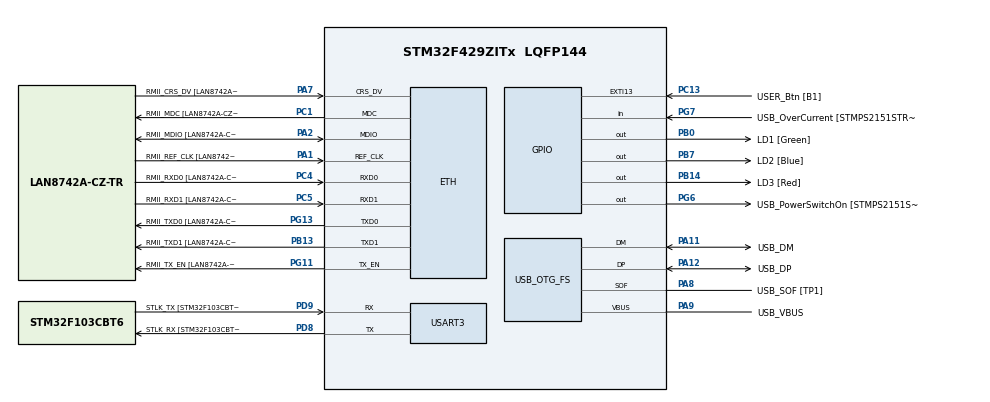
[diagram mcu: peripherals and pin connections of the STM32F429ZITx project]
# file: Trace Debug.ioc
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ETH.MediaInterface=ETH_MEDIA_INTERFACE_RMII
ETH.PHY_Name=LAN8742A_PHY_ADDRESS
ETH.PHY_Value=0
ETH.PhyAddress=0
Mcu.Family=STM32F4
Mcu.Name=STM32F429ZITx
Mcu.Package=LQFP144
NVIC.PriorityGroup=NVIC_PRIORITYGROUP_4
PA1.GPIO_Label=RMII_REF_CLK [LAN8742A-CZ-TR_REFCLK0]
PA1.Mode=RMII
PA1.Signal=ETH_REF_CLK
PA10.GPIO_Label=USB_ID
PA10.Signal=USB_OTG_FS_ID
PA11.GPIO_Label=USB_DM
PA11.Mode=Device_Only
PA11.Signal=USB_OTG_FS_DM
PA12.GPIO_Label=USB_DP
PA12.Mode=Device_Only
PA12.Signal=USB_OTG_FS_DP
PA13.GPIO_Label=TMS
PA13.Mode=Trace_Asynchronous_SW
PA13.Signal=SYS_JTMS-SWDIO
PA14.GPIO_Label=TCK
PA14.Mode=Trace_Asynchronous_SW
PA14.Signal=SYS_JTCK-SWCLK
PA2.GPIO_Label=RMII_MDIO [LAN8742A-CZ-TR_MDIO]
PA2.Mode=RMII
PA2.Signal=ETH_MDIO
PA7.GPIO_Label=RMII_CRS_DV [LAN8742A-CZ-TR_CRS_DV]
PA7.Mode=RMII
PA7.Signal=ETH_CRS_DV
PA8.GPIO_Label=USB_SOF [TP1]
PA8.Mode=Activate_SOF_FS
PA8.Signal=USB_OTG_FS_SOF
PA9.GPIO_Label=USB_VBUS
PA9.Mode=Activate_VBUS
PA9.Signal=USB_OTG_FS_VBUS
PB0.GPIO_Label=LD1 [Green]
PB0.Signal=GPIO_Output
PB13.GPIO_Label=RMII_TXD1 [LAN8742A-CZ-TR_TXD1]
PB13.Mode=RMII
PB13.Signal=ETH_TXD1
PB14.GPIO_Label=LD3 [Red]
PB14.Signal=GPIO_Output
PB3.Mode=Trace_Asynchronous_SW
PB3.Signal=SYS_JTDO-SWO
PB7.GPIO_Label=LD2 [Blue]
PB7.Signal=GPIO_Output
PC1.GPIO_Label=RMII_MDC [LAN8742A-CZ-TR_MDC]
PC1.Mode=RMII
PC1.Signal=ETH_MDC
PC13.GPIO_Label=USER_Btn [B1]
PC13.Signal=GPXTI13
PC14/OSC32_IN.Mode=LSE-External-Oscillator
PC14/OSC32_IN.Signal=RCC_OSC32_IN
PC15/OSC32_OUT.Mode=LSE-External-Oscillator
PC15/OSC32_OUT.Signal=RCC_OSC32_OUT
PC4.GPIO_Label=RMII_RXD0 [LAN8742A-CZ-TR_RXD0]
PC4.Mode=RMII
PC4.Signal=ETH_RXD0
PC5.GPIO_Label=RMII_RXD1 [LAN8742A-CZ-TR_RXD1]
PC5.Mode=RMII
PC5.Signal=ETH_RXD1
PD8.GPIO_Label=STLK_RX [STM32F103CBT6_PA3]
PD8.Mode=Asynchronous
PD8.Signal=USART3_TX
PD9.GPIO_Label=STLK_TX [STM32F103CBT6_PA2]
PD9.Mode=Asynchronous
PD9.Signal=USART3_RX
PG11.GPIO_Label=RMII_TX_EN [LAN8742A-CZ-TR_TXEN]
PG11.Mode=RMII
PG11.Signal=ETH_TX_EN
PG13.GPIO_Label=RMII_TXD0 [LAN8742A-CZ-TR_TXD0]
PG13.Mode=RMII
PG13.Signal=ETH_TXD0
PG6.GPIO_Label=USB_PowerSwitchOn [STMPS2151STR_EN]
PG6.Signal=GPIO_Output
PG7.GPIO_Label=USB_OverCurrent [STMPS2151STR_FAULT]
PG7.Signal=GPIO_Input
PH0/OSC_IN.GPIO_Label=MCO [STM32F103CBT6_PA8]
PH0/OSC_IN.Mode=HSE-External-Clock-Source
PH0/OSC_IN.Signal=RCC_OSC_IN
PH1/OSC_OUT.Mode=HSE-External-Clock-Source
PH1/OSC_OUT.Signal=RCC_OSC_OUT
ProjectManager.HeapSize=0x800
ProjectManager.StackSize=0x800
ProjectManager.TargetToolchain=STM32CubeIDE
RCC.48MHZClocksFreq_Value=48000000
RCC.AHBFreq_Value=168000000
RCC.APB1CLKDivider=RCC_HCLK_DIV4
RCC.APB1Freq_Value=42000000
RCC.APB1TimFreq_Value=84000000
RCC.APB2CLKDivider=RCC_HCLK_DIV2
RCC.APB2Freq_Value=84000000
RCC.APB2TimCLKDivider=2
RCC.APB2TimFreq_Value=168000000
RCC.CortexFreq_Value=168000000
RCC.HCLKFreq_Value=168000000
RCC.HSE_VALUE=8000000
RCC.HSI_VALUE=16000000
RCC.PLLM=4
RCC.PLLMUL=RCC_PLL_MUL9
RCC.PLLN=168
RCC.PLLQ=7
RCC.PRESCALERUSB=RCC_USBCLKSOURCE_PLL_DIV1_5
RCC.SYSCLKFreq_VALUE=168000000
RCC.SYSCLKSource=RCC_SYSCLKSOURCE_PLLCLK
RCC.SYSCLKSourceVirtual=RCC_SYSCLKSOURCE_PLLCLK
RCC.USBFreq_Value=48000000
RCC.VCOOutputFreq_Value=336000000
USART3.VirtualMode=VM_ASYNC
USB_OTG_FS.VirtualMode=Device_Only
board=NUCLEO-F429ZI

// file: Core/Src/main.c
/* USER CODE BEGIN Header */
/**
  ******************************************************************************
  * @file           : main.c
  * @brief          : Main program body
  ******************************************************************************
  * @attention
  *
  * <h2><center>&copy; Copyright (c) 2022 STMicroelectronics.
  * All rights reserved.</center></h2>
  *
  * This software component is licensed by ST under BSD 3-Clause license,
  * the "License"; You may not use this file except in compliance with the
  * License. You may obtain a copy of the License at:
  *                        opensource.org/licenses/BSD-3-Clause
  *
  ******************************************************************************
  */
/* USER CODE END Header */
#include "main.h"
#include "Modules/cramel.h"
#include "dwt_counter.h"
#include "math_helper.h"

ETH_HandleTypeDef heth;

UART_HandleTypeDef huart3;

PCD_HandleTypeDef hpcd_USB_OTG_FS;

void SystemClock_Config(void);
static void MX_GPIO_Init(void);
static void MX_USART3_UART_Init(void);

/* USER CODE BEGIN 0 */
int16_t s16_curfitLine[RX_LEN];
float f32_curfitLine[RX_LEN];

#ifdef SWO_DEBUG
	//make sure SWV core clock MHz same as CPU clock.
	//SWV viewer setting debug port 1 are checked, and started

	int _write(int file, char *ptr, int len)
	{
		int i=0;
		for(i=0; i<len; i++){
			ITM_SendChar(*ptr++);
		}
		return len;
	}

#else
#ifdef __GNUC__
	/* With GCC, small printf (option LD Linker->Libraries->Small printf set to 'Yes') calls __io_putchar() */
	#define PUTCHAR_PROTOTYPE int __io_putchar(int ch)
	#else
	#define PUTCHAR_PROTOTYPE int fputc(int ch, FILE *f)
	#endif /* __GNUC__ */

	/******************************************************************
	  * @name   PUTCHAR_PROTOTYPE
	  * @brief  Retargets the C library printf function to the USART.
	  *****************************************************************/
	PUTCHAR_PROTOTYPE
	{
		HAL_UART_Transmit(&huart3, (uint8_t *)&ch, 1, 0xFFFF);				//Use USART3
		return ch;
	}

#endif

/* USER CODE END 0 */

int main(void)
{
  /* USER CODE BEGIN 1 */
  curfitCoef_t curfitCoef;
  uint64_t u64_bitmap;

  int16_t *s16_src;
  uint8_t *u8_curfitComp;
  float *f32_curfitLineRef;
  float f32_snr;
  float f32_accuracy;
  volatile float f32_duration = 0;
  volatile float f32_accuracyFrame = 0;
  /* USER CODE END 1 */

  /* MCU Configuration--------------------------------------------------------*/

  /* Reset of all peripherals, Initializes the Flash interface and the Systick. */
  HAL_Init();

  /* Configure the system clock */
  SystemClock_Config();

  /* Initialize all configured peripherals */
  MX_GPIO_Init();
  MX_USART3_UART_Init();
  /* USER CODE BEGIN 2 */
  SystemCoreClockUpdate();
  printf("\r\nINIT GCC OK @ %ld MHz\r\n",SystemCoreClock/1000000);
  /* USER CODE END 2 */

  /* Infinite loop */
  /* USER CODE BEGIN WHILE */
  for (uint8_t u8_i = 0; u8_i < TX_LEN; u8_i++)
  {
	  /* Set data */
	  s16_src = (int16_t*) &s16_reconstructed[u8_i];
	  u8_curfitComp = (uint8_t*) &u8_curvefitCompare[u8_i];
	  f32_curfitLineRef = (float*) &f32_curvefitLineRef[u8_i];
	  u64_bitmap = u64Func_GetBitmap(u8_curfitComp, RX_LEN);

	  /* Start timer */
	  DWT_Start();

	  /* Estimate */
	  vFunc_CurfitEstimation(s16_src, &curfitCoef, RX_LEN, u64_bitmap);
	  vFunc_GetCurveFitLine(s16_curfitLine, &curfitCoef, RX_LEN);

	  /* Stop timer */
	  f32_duration += DWT_GetTime_us();
	  DWT_Stop();

	  /* Calculate accuracy */
	  vFunc_ConvertS16toFloat(s16_curfitLine, f32_curfitLine, RX_LEN);
	  f32_snr = arm_snr_f32(f32_curfitLineRef, f32_curfitLine, RX_LEN);
	  f32_accuracy = 100.0f - (100.0f / f32_snr);
	  f32_accuracyFrame += f32_accuracy;

	  /* Print to stdout */
	  printf("Accuracy TX[%d]: %.2f %%\r\n", u8_i, f32_accuracy);
  }

  f32_accuracyFrame /= TX_LEN;
  f32_duration /= 1000;

  printf("\r\n");
  printf("Frame Accuracy: %.2f %%\r\n", f32_accuracyFrame);
  printf("Frame Duration: %.2f ms\r\n", f32_duration);

  while (1)
  {
    /* USER CODE END WHILE */

  }
}

void SystemClock_Config(void)
{
  RCC_OscInitTypeDef RCC_OscInitStruct = {0};
  RCC_ClkInitTypeDef RCC_ClkInitStruct = {0};

  /** Configure the main internal regulator output voltage
  */
  __HAL_RCC_PWR_CLK_ENABLE();
  __HAL_PWR_VOLTAGESCALING_CONFIG(PWR_REGULATOR_VOLTAGE_SCALE1);
  /** Initializes the RCC Oscillators according to the specified parameters
  * in the RCC_OscInitTypeDef structure.
  */
  RCC_OscInitStruct.OscillatorType = RCC_OSCILLATORTYPE_HSE;
  RCC_OscInitStruct.HSEState = RCC_HSE_BYPASS;
  RCC_OscInitStruct.PLL.PLLState = RCC_PLL_ON;
  RCC_OscInitStruct.PLL.PLLSource = RCC_PLLSOURCE_HSE;
  RCC_OscInitStruct.PLL.PLLM = 4;
  RCC_OscInitStruct.PLL.PLLN = 68;
  RCC_OscInitStruct.PLL.PLLP = RCC_PLLP_DIV2;
  RCC_OscInitStruct.PLL.PLLQ = 7;
  if (HAL_RCC_OscConfig(&RCC_OscInitStruct) != HAL_OK)
  {
    Error_Handler();
  }
  /** Initializes the CPU, AHB and APB buses clocks
  */
  RCC_ClkInitStruct.ClockType = RCC_CLOCKTYPE_HCLK|RCC_CLOCKTYPE_SYSCLK
                              |RCC_CLOCKTYPE_PCLK1|RCC_CLOCKTYPE_PCLK2;
  RCC_ClkInitStruct.SYSCLKSource = RCC_SYSCLKSOURCE_PLLCLK;
  RCC_ClkInitStruct.AHBCLKDivider = RCC_SYSCLK_DIV1;
  RCC_ClkInitStruct.APB1CLKDivider = RCC_HCLK_DIV4;
  RCC_ClkInitStruct.APB2CLKDivider = RCC_HCLK_DIV2;

  if (HAL_RCC_ClockConfig(&RCC_ClkInitStruct, FLASH_LATENCY_5) != HAL_OK)
  {
    Error_Handler();
  }
}

static void MX_USART3_UART_Init(void)
{

  huart3.Instance = USART3;
  huart3.Init.BaudRate = 115200;
  huart3.Init.WordLength = UART_WORDLENGTH_8B;
  huart3.Init.StopBits = UART_STOPBITS_1;
  huart3.Init.Parity = UART_PARITY_NONE;
  huart3.Init.Mode = UART_MODE_TX_RX;
  huart3.Init.HwFlowCtl = UART_HWCONTROL_NONE;
  huart3.Init.OverSampling = UART_OVERSAMPLING_16;
  if (HAL_UART_Init(&huart3) != HAL_OK)
  {
    Error_Handler();
  }

}

static void MX_GPIO_Init(void)
{
  GPIO_InitTypeDef GPIO_InitStruct = {0};

  /* GPIO Ports Clock Enable */
  __HAL_RCC_GPIOC_CLK_ENABLE();
  __HAL_RCC_GPIOH_CLK_ENABLE();
  __HAL_RCC_GPIOA_CLK_ENABLE();
  __HAL_RCC_GPIOB_CLK_ENABLE();
  __HAL_RCC_GPIOD_CLK_ENABLE();
  __HAL_RCC_GPIOG_CLK_ENABLE();

  /*Configure GPIO pin Output Level */
  HAL_GPIO_WritePin(GPIOB, LD1_Pin|LD3_Pin|LD2_Pin, GPIO_PIN_RESET);

  /*Configure GPIO pin Output Level */
  HAL_GPIO_WritePin(USB_PowerSwitchOn_GPIO_Port, USB_PowerSwitchOn_Pin, GPIO_PIN_RESET);

  /*Configure GPIO pin : USER_Btn_Pin */
  GPIO_InitStruct.Pin = USER_Btn_Pin;
  GPIO_InitStruct.Mode = GPIO_MODE_IT_RISING;
  GPIO_InitStruct.Pull = GPIO_NOPULL;
  HAL_GPIO_Init(USER_Btn_GPIO_Port, &GPIO_InitStruct);

  /*Configure GPIO pins : LD1_Pin LD3_Pin LD2_Pin */
  GPIO_InitStruct.Pin = LD1_Pin|LD3_Pin|LD2_Pin;
  GPIO_InitStruct.Mode = GPIO_MODE_OUTPUT_PP;
  GPIO_InitStruct.Pull = GPIO_NOPULL;
  GPIO_InitStruct.Speed = GPIO_SPEED_FREQ_LOW;
  HAL_GPIO_Init(GPIOB, &GPIO_InitStruct);

  /*Configure GPIO pin : USB_PowerSwitchOn_Pin */
  GPIO_InitStruct.Pin = USB_PowerSwitchOn_Pin;
  GPIO_InitStruct.Mode = GPIO_MODE_OUTPUT_PP;
  GPIO_InitStruct.Pull = GPIO_NOPULL;
  GPIO_InitStruct.Speed = GPIO_SPEED_FREQ_LOW;
  HAL_GPIO_Init(USB_PowerSwitchOn_GPIO_Port, &GPIO_InitStruct);

  /*Configure GPIO pin : USB_OverCurrent_Pin */
  GPIO_InitStruct.Pin = USB_OverCurrent_Pin;
  GPIO_InitStruct.Mode = GPIO_MODE_INPUT;
  GPIO_InitStruct.Pull = GPIO_NOPULL;
  HAL_GPIO_Init(USB_OverCurrent_GPIO_Port, &GPIO_InitStruct);

}

void Error_Handler(void)
{
  __disable_irq();
  while (1)
  {
  }
}

/************************ (C) COPYRIGHT STMicroelectronics *****END OF FILE****/
